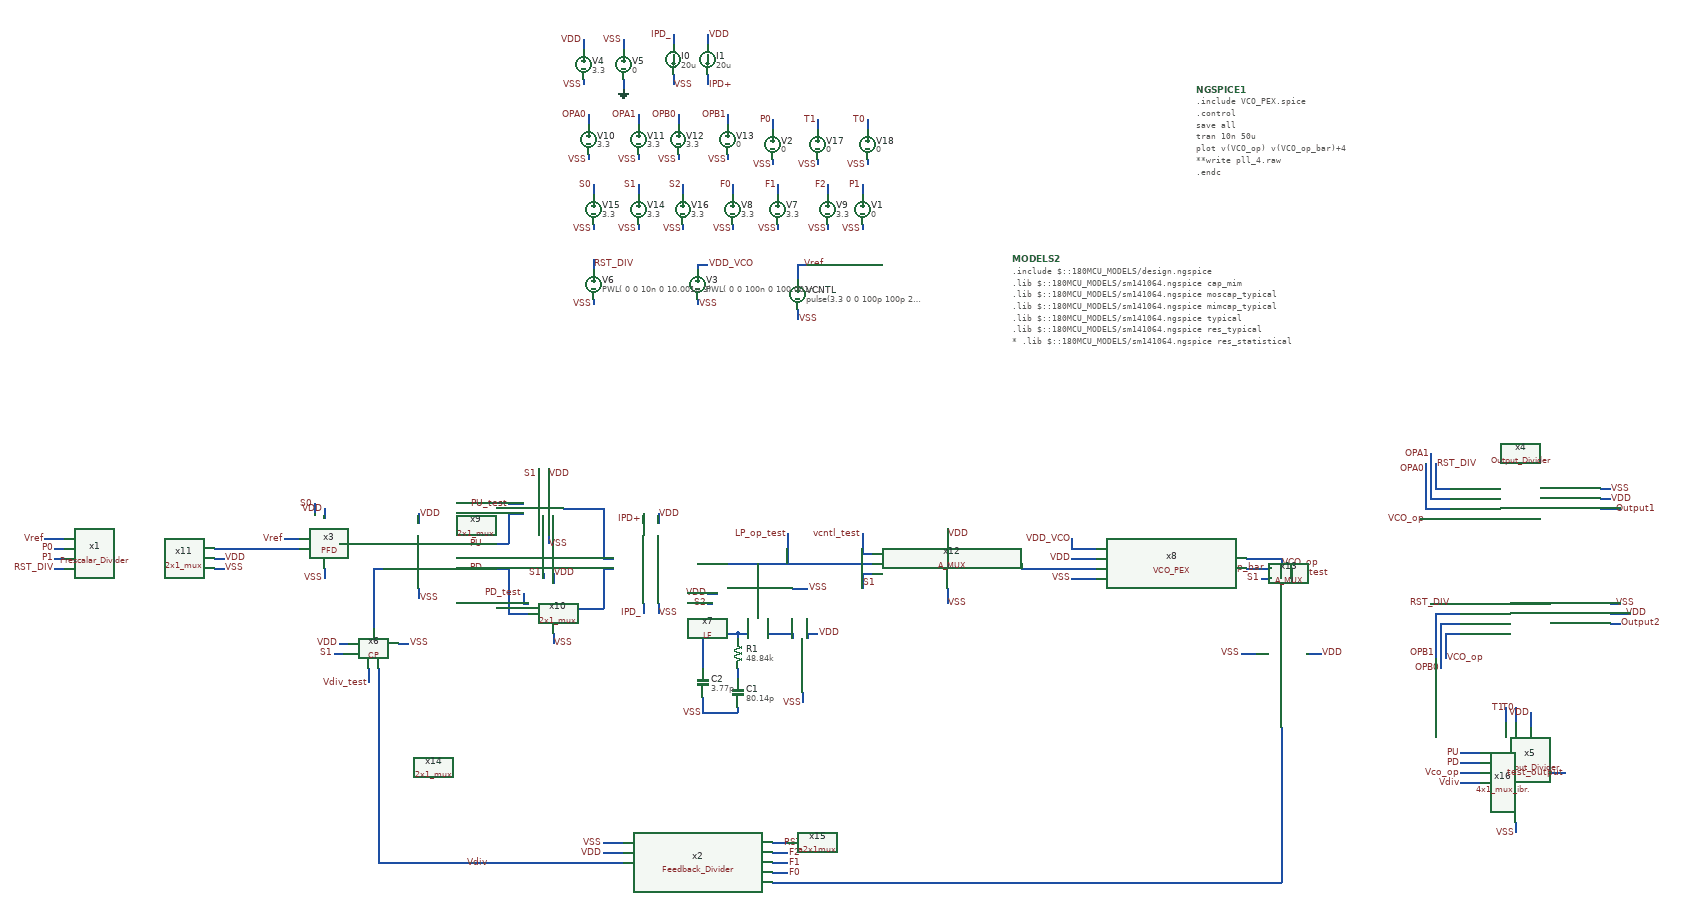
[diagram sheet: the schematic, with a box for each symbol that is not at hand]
v {xschem version=3.1.0 file_version=1.2
}
G {}
K {}
V {}
S {}
E {}
N 300 -1020 320 -1020 {
lab=P0}
N 300 -1000 320 -1000 {
lab=P1}
N 300 -980 320 -980 {
lab=RST_DIV}
N 620 -980 640 -980 {
lab=VSS}
N 620 -1000 640 -1000 {
lab=VDD}
N 1920 -1670 1920 -1660 {
lab=VSS}
N 1920 -1750 1920 -1730 {
lab=P1}
N 1740 -1800 1740 -1790 {
lab=VSS}
N 1740 -1880 1740 -1860 {
lab=P0}
N 1030 -1090 1030 -1070 {
lab=VDD}
N 1030 -940 1030 -920 {
lab=VSS}
N 940 -1030 960 -1030 {
lab=#net1}
N 940 -980 960 -980 {
lab=#net2}
N 1100 -980 1120 -980 {
lab=PD}
N 1120 -1030 1210 -1030 {
lab=PU}
N 1120 -980 1210 -980 {
lab=PD}
N 1150 -390 1440 -390 {
lab=Vdiv}
N 2340 -1020 2380 -1020 {
lab=VDD_VCO}
N 1100 -1030 1120 -1030 {
lab=PU}
N 1790 -1500 1790 -1480 {
lab=VSS}
N 1590 -1520 1590 -1510 {
lab=VSS}
N 1790 -1590 1810 -1590 {
lab=Vref}
N 1360 -1960 1360 -1950 {
lab=VSS}
N 1360 -2040 1360 -2020 {
lab=VDD}
N 1440 -2040 1440 -2020 {
lab=VSS}
N 1440 -1960 1440 -1940 {
lab=GND}
N 2340 -1040 2340 -1020 {
lab=VDD_VCO}
N 1400 -430 1440 -430 {
lab=VSS}
N 1400 -410 1440 -410 {
lab=VDD}
N 1740 -410 1770 -410 {
lab=F2}
N 1740 -430 1770 -430 {
lab=RST_DIV}
N 1380 -1520 1380 -1510 {
lab=VSS}
N 1380 -1600 1380 -1580 {
lab=RST_DIV}
N 2380 -1020 2390 -1020 {
lab=VDD_VCO}
N 1740 -370 1770 -370 {
lab=F0}
N 1740 -390 1770 -390 {
lab=F1}
N 1590 -1590 1590 -1580 {
lab=VDD_VCO}
N 1590 -1590 1610 -1590 {
lab=VDD_VCO}
N 1750 -1670 1750 -1660 {
lab=VSS}
N 1750 -1750 1750 -1730 {
lab=F1}
N 1660 -1670 1660 -1660 {
lab=VSS}
N 1660 -1750 1660 -1730 {
lab=F0}
N 1850 -1670 1850 -1660 {
lab=VSS}
N 1850 -1750 1850 -1730 {
lab=F2}
N 3070 -1140 3100 -1140 {
lab=RST_DIV}
N 3070 -1190 3070 -1140 {
lab=RST_DIV}
N 3040 -1080 3100 -1080 {
lab=VCO_op}
N 3060 -1120 3100 -1120 {
lab=OPA1}
N 3060 -1190 3060 -1120 {
lab=OPA1}
N 3050 -1100 3100 -1100 {
lab=OPA0}
N 3050 -1190 3050 -1100 {
lab=OPA0}
N 3400 -1140 3420 -1140 {
lab=VSS}
N 3400 -1120 3420 -1120 {
lab=VDD}
N 3400 -1100 3440 -1100 {
lab=Output1}
N 3060 -1210 3060 -1190 {
lab=OPA1}
N 3090 -850 3120 -850 {
lab=VCO_op}
N 3090 -850 3090 -800 {
lab=VCO_op}
N 3060 -910 3120 -910 {
lab=RST_DIV}
N 3080 -870 3120 -870 {
lab=OPB0}
N 3080 -870 3080 -800 {
lab=OPB0}
N 3070 -890 3120 -890 {
lab=OPB1}
N 3070 -890 3070 -800 {
lab=OPB1}
N 3420 -910 3440 -910 {
lab=VSS}
N 3420 -870 3440 -870 {
lab=Output2}
N 3420 -890 3460 -890 {
lab=VDD}
N 3080 -800 3080 -780 {
lab=OPB0}
N 1370 -1810 1370 -1800 {
lab=VSS}
N 1370 -1890 1370 -1870 {
lab=OPA0}
N 1470 -1810 1470 -1800 {
lab=VSS}
N 1470 -1890 1470 -1870 {
lab=OPA1}
N 1550 -1810 1550 -1800 {
lab=VSS}
N 1550 -1890 1550 -1870 {
lab=OPB0}
N 1650 -1810 1650 -1800 {
lab=VSS}
N 1650 -1890 1650 -1870 {
lab=OPB1}
N 1510 -1090 1510 -1070 {
lab=VDD}
N 1510 -910 1510 -890 {
lab=VSS}
N 1400 -1000 1420 -1000 {
lab=#net3}
N 1400 -980 1420 -980 {
lab=#net4}
N 1480 -1090 1480 -1070 {
lab=IPD+}
N 1480 -910 1480 -890 {
lab=IPD_}
N 1540 -1970 1540 -1950 {
lab=VSS}
N 1610 -1970 1610 -1950 {
lab=IPD+}
N 1540 -2050 1540 -2030 {
lab=IPD_}
N 1610 -2050 1610 -2030 {
lab=VDD}
N 710 -1020 740 -1020 {
lab=#net5}
N 280 -1040 310 -1040 {
lab=Vref}
N 620 -1020 690 -1020 {
lab=#net5}
N 690 -1020 710 -1020 {
lab=#net5}
N 310 -1040 320 -1040 {
lab=Vref}
N 1210 -980 1210 -890 {
lab=PD}
N 1210 -890 1250 -890 {
lab=PD}
N 1240 -910 1250 -910 {
lab=PD_test}
N 1240 -930 1240 -910 {
lab=PD_test}
N 1210 -1090 1210 -1030 {
lab=PU}
N 1210 -1090 1240 -1090 {
lab=PU}
N 1290 -1050 1290 -1030 {
lab=VSS}
N 1280 -970 1280 -960 {
lab=S1}
N 1300 -970 1300 -950 {
lab=VDD}
N 1320 -1100 1400 -1100 {
lab=#net3}
N 1400 -1100 1400 -1030 {
lab=#net3}
N 1400 -980 1400 -900 {
lab=#net4}
N 1330 -900 1400 -900 {
lab=#net4}
N 1400 -1030 1400 -1000 {
lab=#net3}
N 1270 -1180 1270 -1160 {
lab=S1}
N 1290 -1180 1290 -1150 {
lab=VDD}
N 1210 -1110 1240 -1110 {
lab=PU_test}
N 1300 -850 1300 -830 {
lab=VSS}
N 840 -980 840 -960 {
lab=VSS}
N 840 -1100 840 -1080 {
lab=VDD}
N 820 -1110 820 -1090 {
lab=S0}
N 740 -1020 790 -1020 {
lab=#net5}
N 760 -1040 790 -1040 {
lab=Vref}
N 1470 -1670 1470 -1660 {
lab=VSS}
N 1470 -1750 1470 -1730 {
lab=S1}
N 2090 -1060 2090 -1040 {
lab=VDD}
N 2090 -940 2090 -910 {
lab=VSS}
N 1920 -1010 1940 -1010 {
lab=vcntl_test}
N 1920 -1050 1920 -1010 {
lab=vcntl_test}
N 1920 -970 1940 -970 {
lab=S1}
N 1920 -970 1920 -940 {
lab=S1}
N 2780 -980 2780 -960 {
lab=Vo_test}
N 2760 -370 2760 -360 {
lab=#net6}
N 2680 -810 2710 -810 {
lab=VSS}
N 2810 -810 2840 -810 {
lab=VDD}
N 2720 -960 2740 -960 {
lab=S1}
N 2760 -360 2760 -350 {
lab=#net6}
N 2410 -350 2760 -350 {
lab=#net6}
N 1740 -350 2410 -350 {
lab=#net6}
N 1790 -1590 1790 -1560 {
lab=Vref}
N 2240 -980 2390 -980 {
lab=#net7}
N 2240 -990 2240 -980 {
lab=#net7}
N 2340 -1000 2390 -1000 {
lab=VDD}
N 2340 -960 2390 -960 {
lab=VSS}
N 2690 -1000 2760 -1000 {
lab=VCO_op}
N 2690 -980 2740 -980 {
lab=VCO_op_bar}
N 2760 -1000 2760 -960 {
lab=VCO_op}
N 870 -1030 930 -1030 {
lab=#net1}
N 990 -830 1010 -830 {
lab=VSS}
N 870 -830 890 -830 {
lab=VDD}
N 860 -810 880 -810 {
lab=S1}
N 950 -780 950 -730 {
lab=Vdiv}
N 930 -780 930 -750 {
lab=Vdiv_test}
N 940 -920 940 -860 {
lab=#net2}
N 950 -730 950 -680 {
lab=Vdiv}
N 940 -980 940 -920 {
lab=#net2}
N 930 -1030 940 -1030 {
lab=#net1}
N 1380 -1670 1380 -1660 {
lab=VSS}
N 1380 -1750 1380 -1730 {
lab=S0}
N 1800 -730 1800 -710 {
lab=VSS}
N 1810 -850 1810 -840 {
lab=VDD}
N 1810 -850 1830 -850 {
lab=VDD}
N 1610 -930 1630 -930 {
lab=VDD}
N 1780 -940 1810 -940 {
lab=VSS}
N 1600 -720 1600 -690 {
lab=VSS}
N 1600 -690 1670 -690 {
lab=VSS}
N 1600 -850 1600 -780 {
lab=#net8}
N 1600 -850 1670 -850 {
lab=#net8}
N 1670 -850 1670 -840 {
lab=#net8}
N 1670 -780 1670 -760 {
lab=#net9}
N 1670 -700 1670 -690 {
lab=VSS}
N 1670 -850 1690 -850 {
lab=#net8}
N 1690 -880 1690 -850 {
lab=#net8}
N 1780 -850 1780 -840 {
lab=#net10}
N 1730 -850 1780 -850 {
lab=#net10}
N 1730 -880 1730 -850 {
lab=#net10}
N 1710 -990 1710 -980 {
lab=LP_op_test}
N 950 -390 1150 -390 {
lab=Vdiv}
N 950 -680 950 -560 {
lab=Vdiv}
N 2760 -490 2760 -370 {
lab=#net6}
N 950 -560 950 -390 {
lab=Vdiv}
N 2760 -660 2760 -500 {
lab=#net6}
N 2760 -500 2760 -490 {
lab=#net6}
N 1560 -1670 1560 -1660 {
lab=VSS}
N 1560 -1750 1560 -1730 {
lab=S2}
N 1610 -910 1620 -910 {
lab=S2}
N 1590 -990 1940 -990 {
lab=LP_op_test}
N 3120 -610 3160 -610 {
lab=#net11}
N 3120 -590 3160 -590 {
lab=#net12}
N 3120 -570 3160 -570 {
lab=#net13}
N 3120 -550 3160 -550 {
lab=#net14}
N 1770 -1050 1770 -990 {}
N 3260 -690 3260 -660 {}
N 3230 -700 3230 -670 {}
N 3210 -700 3210 -670 {}
N 3230 -470 3230 -450 {}
N 3300 -570 3330 -570 {}
N 1830 -1800 1830 -1790 {
lab=VSS}
N 1830 -1880 1830 -1860 {
lab=P1}
N 1930 -1800 1930 -1790 {
lab=VSS}
N 1930 -1880 1930 -1860 {
lab=P0}
C {devices/lab_pin.sym} 300 -1000 0 0 {name=p139 sig_type=std_logic lab=P1}
C {devices/lab_pin.sym} 300 -1020 0 0 {name=p140 sig_type=std_logic lab=P0}
C {devices/lab_pin.sym} 280 -1040 0 0 {name=p141 sig_type=std_logic lab=Vref
}
C {devices/lab_pin.sym} 640 -980 2 0 {name=p142 sig_type=std_logic lab=VSS}
C {devices/lab_pin.sym} 640 -1000 2 0 {name=p143 sig_type=std_logic lab=VDD}
C {devices/lab_pin.sym} 300 -980 0 0 {name=p144 sig_type=std_logic lab=RST_DIV}
C {devices/vsource.sym} 1920 -1700 0 0 {name=V1 value=0}
C {devices/lab_wire.sym} 1920 -1660 0 0 {name=p1 sig_type=std_logic lab=VSS
}
C {devices/lab_wire.sym} 1920 -1750 0 0 {name=p2 sig_type=std_logic lab=P1}
C {devices/vsource.sym} 1740 -1830 0 0 {name=V2 value=0}
C {devices/lab_wire.sym} 1740 -1790 0 0 {name=p3 sig_type=std_logic lab=VSS
}
C {devices/lab_wire.sym} 1740 -1880 0 0 {name=p4 sig_type=std_logic lab=P0}
C {PFD.sym} 740 -820 0 0 {name=x3}
C {devices/lab_pin.sym} 1030 -1090 2 0 {name=p9 sig_type=std_logic lab=VDD}
C {devices/lab_wire.sym} 1030 -920 2 0 {name=p10 sig_type=std_logic lab=VSS}
C {devices/lab_pin.sym} 1170 -390 1 0 {name=p28 sig_type=std_logic lab=Vdiv
}
C {devices/vsource.sym} 1790 -1530 0 0 {name=VCNTL value="pulse(3.3 0 0 100p 100p 250n 500n)"}
C {devices/vsource.sym} 1590 -1550 0 0 {name=V3 value=" PWL( 0 0 100n 0 100.001n 3.3)"}
C {devices/code_shown.sym} 2590 -1940 0 1 {name=NGSPICE1 only_toplevel=true
value="
.include "VCO_PEX.spice"
.control
save all
tran 10n 50u 
plot v(VCO_op) v(VCO_op_bar)+4
**write pll_4.raw
.endc
"}
C {devices/vsource.sym} 1360 -1990 0 0 {name=V4 value=3.3}
C {devices/vsource.sym} 1440 -1990 0 0 {name=V5 value=0}
C {devices/lab_wire.sym} 1440 -2040 0 0 {name=p7 sig_type=std_logic lab=VSS}
C {devices/lab_wire.sym} 1360 -1950 0 0 {name=p8 sig_type=std_logic lab=VSS
}
C {devices/lab_wire.sym} 1360 -2040 0 0 {name=p11 sig_type=std_logic lab=VDD}
C {devices/gnd.sym} 1440 -1940 0 0 {name=l3 lab=GND}
C {devices/lab_pin.sym} 2340 -1040 0 0 {name=p12 sig_type=std_logic lab=VDD_VCO}
C {devices/lab_pin.sym} 2730 -980 1 0 {name=p13 sig_type=std_logic lab=VCO_op_bar
}
C {devices/lab_pin.sym} 1400 -410 0 0 {name=p14 sig_type=std_logic lab=VDD}
C {devices/lab_wire.sym} 1400 -430 1 0 {name=p15 sig_type=std_logic lab=VSS}
C {devices/lab_pin.sym} 1610 -1590 2 0 {name=p16 sig_type=std_logic lab=VDD_VCO}
C {devices/lab_pin.sym} 1800 -1590 2 0 {name=p17 sig_type=std_logic lab=Vref
}
C {devices/lab_wire.sym} 1380 -1510 0 0 {name=p18 sig_type=std_logic lab=VSS
}
C {devices/vsource.sym} 1380 -1550 0 0 {name=V6 value=" PWL( 0 0 10n 0 10.001n 3)"}
C {devices/lab_pin.sym} 1770 -1050 1 0 {name=p19 sig_type=std_logic lab=LP_op_test
}
C {devices/lab_pin.sym} 1160 -1030 1 0 {name=p20 sig_type=std_logic lab=PU}
C {devices/lab_pin.sym} 1160 -980 1 0 {name=p21 sig_type=std_logic lab=PD}
C {Feedback_Divider.sym} 1590 -390 0 1 {name=x2}
C {devices/lab_pin.sym} 1770 -370 2 0 {name=p22 sig_type=std_logic lab=F0}
C {devices/lab_pin.sym} 1770 -390 2 0 {name=p23 sig_type=std_logic lab=F1}
C {devices/lab_pin.sym} 1770 -410 2 0 {name=p24 sig_type=std_logic lab=F2}
C {devices/vsource.sym} 1750 -1700 0 0 {name=V7 value=3.3}
C {devices/lab_wire.sym} 1750 -1660 0 0 {name=p26 sig_type=std_logic lab=VSS
}
C {devices/lab_wire.sym} 1750 -1750 0 0 {name=p27 sig_type=std_logic lab=F1}
C {devices/vsource.sym} 1660 -1700 0 0 {name=V8 value=3.3}
C {devices/lab_wire.sym} 1660 -1660 0 0 {name=p25 sig_type=std_logic lab=VSS
}
C {devices/lab_wire.sym} 1660 -1750 0 0 {name=p29 sig_type=std_logic lab=F0}
C {devices/vsource.sym} 1850 -1700 0 0 {name=V9 value=3.3}
C {devices/lab_wire.sym} 1850 -1660 0 0 {name=p30 sig_type=std_logic lab=VSS
}
C {devices/lab_wire.sym} 1850 -1750 0 0 {name=p31 sig_type=std_logic lab=F2}
C {devices/lab_pin.sym} 3420 -1120 2 0 {name=p32 sig_type=std_logic lab=VDD}
C {devices/lab_pin.sym} 3420 -1140 2 0 {name=p33 sig_type=std_logic lab=VSS}
C {devices/lab_wire.sym} 3050 -1180 0 0 {name=p82 sig_type=std_logic lab=OPA0}
C {devices/lab_wire.sym} 3060 -1210 0 0 {name=p83 sig_type=std_logic lab=OPA1}
C {devices/lab_pin.sym} 3070 -1190 2 0 {name=p34 sig_type=std_logic lab=RST_DIV}
C {devices/lab_pin.sym} 3430 -1100 2 0 {name=p84 sig_type=std_logic lab=Output1}
C {devices/lab_pin.sym} 3450 -890 0 1 {name=p85 sig_type=std_logic lab=VDD}
C {devices/lab_pin.sym} 3430 -910 0 1 {name=p86 sig_type=std_logic lab=VSS}
C {devices/lab_wire.sym} 3070 -810 2 1 {name=p87 sig_type=std_logic lab=OPB1}
C {devices/lab_wire.sym} 3080 -780 2 1 {name=p88 sig_type=std_logic lab=OPB0}
C {devices/lab_pin.sym} 3440 -870 0 1 {name=p90 sig_type=std_logic lab=Output2}
C {Output_Divider.sym} 3270 -880 0 0 {name=x5}
C {devices/lab_pin.sym} 3100 -910 1 0 {name=p35 sig_type=std_logic lab=RST_DIV}
C {devices/lab_pin.sym} 3090 -800 2 0 {name=p37 sig_type=std_logic lab=VCO_op
}
C {devices/lab_pin.sym} 3050 -1080 2 1 {name=p40 sig_type=std_logic lab=VCO_op
}
C {devices/vsource.sym} 1370 -1840 0 0 {name=V10 value=3.3}
C {devices/lab_wire.sym} 1370 -1800 0 0 {name=p41 sig_type=std_logic lab=VSS
}
C {devices/lab_wire.sym} 1370 -1890 0 0 {name=p42 sig_type=std_logic lab=OPA0}
C {devices/vsource.sym} 1470 -1840 0 0 {name=V11 value=3.3}
C {devices/lab_wire.sym} 1470 -1800 0 0 {name=p43 sig_type=std_logic lab=VSS
}
C {devices/lab_wire.sym} 1470 -1890 0 0 {name=p44 sig_type=std_logic lab=OPA1}
C {devices/vsource.sym} 1550 -1840 0 0 {name=V12 value=3.3}
C {devices/lab_wire.sym} 1550 -1800 0 0 {name=p45 sig_type=std_logic lab=VSS
}
C {devices/lab_wire.sym} 1550 -1890 0 0 {name=p46 sig_type=std_logic lab=OPB0
}
C {devices/vsource.sym} 1650 -1840 0 0 {name=V13 value=0}
C {devices/lab_wire.sym} 1650 -1800 0 0 {name=p47 sig_type=std_logic lab=VSS
}
C {devices/lab_wire.sym} 1650 -1890 0 0 {name=p48 sig_type=std_logic lab=OPB1}
C {devices/lab_pin.sym} 1380 -1590 2 0 {name=p38 sig_type=std_logic lab=RST_DIV}
C {devices/lab_pin.sym} 1760 -430 2 0 {name=p39 sig_type=std_logic lab=RST_DIV}
C {devices/lab_wire.sym} 1510 -890 2 0 {name=p49 sig_type=std_logic lab=VSS}
C {devices/lab_pin.sym} 1510 -1090 2 0 {name=p50 sig_type=std_logic lab=VDD}
C {CP.sym} 930 -790 0 0 {name=x6}
C {devices/lab_wire.sym} 1480 -1080 0 0 {name=p52 sig_type=std_logic lab=IPD+}
C {devices/lab_wire.sym} 1480 -890 0 0 {name=p53 sig_type=std_logic lab=IPD_}
C {devices/isource.sym} 1540 -2000 0 0 {name=I0 value=20u}
C {devices/isource.sym} 1610 -2000 0 0 {name=I1 value=20u}
C {devices/lab_wire.sym} 1540 -2050 0 0 {name=p54 sig_type=std_logic lab=IPD_}
C {devices/lab_wire.sym} 1610 -1950 2 0 {name=p55 sig_type=std_logic lab=IPD+}
C {devices/lab_wire.sym} 1540 -1950 2 0 {name=p56 sig_type=std_logic lab=VSS}
C {devices/lab_wire.sym} 1610 -2050 2 0 {name=p57 sig_type=std_logic lab=VDD}
C {Output_Divider.sym} 3250 -1110 0 0 {name=x4}
C {devices/code_shown.sym} 2220 -1600 0 0 {name=MODELS2 only_toplevel=true
format="tcleval( @value )"
value="
.include $::180MCU_MODELS/design.ngspice
.lib $::180MCU_MODELS/sm141064.ngspice cap_mim
.lib $::180MCU_MODELS/sm141064.ngspice moscap_typical
.lib $::180MCU_MODELS/sm141064.ngspice mimcap_typical
.lib $::180MCU_MODELS/sm141064.ngspice typical
.lib $::180MCU_MODELS/sm141064.ngspice res_typical
* .lib $::180MCU_MODELS/sm141064.ngspice res_statistical
"}
C {Prescalar_Divider.sym} 470 -1010 2 1 {name=x1}
C {devices/lab_wire.sym} 1590 -1510 2 0 {name=p5 sig_type=std_logic lab=VSS
}
C {devices/lab_wire.sym} 1790 -1480 2 0 {name=p6 sig_type=std_logic lab=VSS
}
C {2x1_mux.sym} 1040 -980 0 0 {name=x9}
C {2x1_mux.sym} 1050 -780 0 0 {name=x10}
C {devices/lab_pin.sym} 1210 -1110 0 0 {name=p60 sig_type=std_logic lab=PU_test
}
C {devices/lab_pin.sym} 1240 -930 1 0 {name=p61 sig_type=std_logic lab=PD_test
}
C {devices/lab_pin.sym} 1290 -1170 2 0 {name=p62 sig_type=std_logic lab=VDD}
C {devices/lab_pin.sym} 1300 -970 2 0 {name=p63 sig_type=std_logic lab=VDD}
C {devices/lab_wire.sym} 1300 -830 2 0 {name=p64 sig_type=std_logic lab=VSS}
C {devices/lab_wire.sym} 1290 -1030 2 0 {name=p65 sig_type=std_logic lab=VSS}
C {devices/lab_pin.sym} 1270 -1170 1 0 {name=p106 sig_type=std_logic lab=S1}
C {devices/lab_pin.sym} 1280 -970 1 0 {name=p66 sig_type=std_logic lab=S1}
C {2x1_mux.sym} 590 -910 0 0 {name=x11}
C {devices/lab_wire.sym} 840 -960 3 0 {name=p67 sig_type=std_logic lab=VSS}
C {devices/lab_pin.sym} 840 -1100 3 1 {name=p68 sig_type=std_logic lab=VDD}
C {devices/lab_pin.sym} 820 -1110 1 0 {name=p69 sig_type=std_logic lab=S0}
C {devices/lab_pin.sym} 760 -1040 1 0 {name=p70 sig_type=std_logic lab=Vref
}
C {devices/vsource.sym} 1470 -1700 0 0 {name=V14 value=3.3}
C {devices/lab_wire.sym} 1470 -1660 0 0 {name=p71 sig_type=std_logic lab=VSS
}
C {devices/lab_wire.sym} 1470 -1750 0 0 {name=p72 sig_type=std_logic lab=S1}
C {A_MUX.sym} 2090 -990 0 0 {name=x12}
C {devices/lab_pin.sym} 2090 -1050 2 0 {name=p73 sig_type=std_logic lab=VDD}
C {devices/lab_wire.sym} 2090 -910 2 0 {name=p74 sig_type=std_logic lab=VSS}
C {devices/lab_pin.sym} 1920 -950 2 0 {name=p75 sig_type=std_logic lab=S1}
C {devices/lab_pin.sym} 1920 -1050 0 0 {name=p76 sig_type=std_logic lab=vcntl_test
}
C {devices/lab_pin.sym} 2760 -990 2 0 {name=p77 sig_type=std_logic lab=VCO_op
}
C {devices/lab_pin.sym} 2780 -970 2 0 {name=p78 sig_type=std_logic lab=Vo_test
}
C {A_MUX.sym} 2760 -810 1 0 {name=x13}
C {devices/lab_pin.sym} 2720 -960 0 0 {name=p79 sig_type=std_logic lab=S1}
C {devices/lab_wire.sym} 2680 -810 0 0 {name=p36 sig_type=std_logic lab=VSS}
C {devices/lab_pin.sym} 2840 -810 2 0 {name=p80 sig_type=std_logic lab=VDD}
C {devices/lab_pin.sym} 2340 -1000 0 0 {name=p81 sig_type=std_logic lab=VDD}
C {devices/lab_wire.sym} 2340 -960 2 1 {name=p89 sig_type=std_logic lab=VSS}
C {2x1_mux.sym} 1060 -580 3 0 {name=x14}
C {devices/lab_wire.sym} 1010 -830 2 0 {name=p91 sig_type=std_logic lab=VSS}
C {devices/lab_pin.sym} 870 -830 2 1 {name=p92 sig_type=std_logic lab=VDD}
C {devices/lab_pin.sym} 860 -810 0 0 {name=p93 sig_type=std_logic lab=S1}
C {devices/lab_pin.sym} 930 -750 0 0 {name=p94 sig_type=std_logic lab=Vdiv_test

}
C {devices/vsource.sym} 1380 -1700 0 0 {name=V15 value=3.3}
C {devices/lab_wire.sym} 1380 -1660 0 0 {name=p95 sig_type=std_logic lab=VSS
}
C {devices/lab_wire.sym} 1380 -1750 0 0 {name=p96 sig_type=std_logic lab=S0}
C {devices/lab_wire.sym} 1800 -710 2 1 {name=p58 sig_type=std_logic lab=VSS}
C {devices/lab_wire.sym} 1830 -850 0 1 {name=p98 sig_type=std_logic lab=VDD}
C {devices/lab_wire.sym} 1810 -940 2 0 {name=p99 sig_type=std_logic lab=VSS}
C {devices/lab_wire.sym} 1610 -930 2 1 {name=p100 sig_type=std_logic lab=VDD}
C {devices/lab_wire.sym} 1610 -910 1 1 {name=p101 sig_type=std_logic lab=S2}
C {devices/capa.sym} 1670 -730 0 0 {name=C1
m=1
value=80.14p
footprint=1206
device="ceramic capacitor"}
C {devices/capa.sym} 1600 -750 0 0 {name=C2
m=1
value=3.77p
footprint=1206
device="ceramic capacitor"}
C {devices/res.sym} 1670 -810 0 0 {name=R1
value=48.84k
footprint=1206
device=resistor
m=1}
C {devices/lab_wire.sym} 1600 -690 2 1 {name=p102 sig_type=std_logic lab=VSS}
C {LF.sym} 1940 -680 0 1 {name=x7}
C {a2x1mux.sym} 1870 -560 3 0 {name=x15}
C {devices/vsource.sym} 1560 -1700 0 0 {name=V16 value=3.3}
C {devices/lab_wire.sym} 1560 -1660 0 0 {name=p51 sig_type=std_logic lab=VSS
}
C {devices/lab_wire.sym} 1560 -1750 0 0 {name=p59 sig_type=std_logic lab=S2}
C {VCO_PEX.sym} 2540 -990 0 0 {name=x8}
C {4x1_mux_ibr..sym} 2880 -460 0 0 {name=x16}
C {devices/lab_pin.sym} 3120 -610 0 0 {name=p97 sig_type=std_logic lab=PU}
C {devices/lab_pin.sym} 3120 -590 0 0 {name=p103 sig_type=std_logic lab=PD}
C {devices/lab_pin.sym} 3120 -570 0 0 {name=p104 sig_type=std_logic lab=Vco_op
}
C {devices/lab_pin.sym} 3120 -550 0 0 {name=p105 sig_type=std_logic lab=Vdiv
}
C {devices/lab_pin.sym} 3210 -700 1 0 {name=p107 sig_type=std_logic lab=T1}
C {devices/lab_pin.sym} 3230 -700 1 0 {name=p108 sig_type=std_logic lab=T0}
C {devices/lab_pin.sym} 3260 -690 3 1 {name=p109 sig_type=std_logic lab=VDD}
C {devices/lab_wire.sym} 3230 -450 3 0 {name=p110 sig_type=std_logic lab=VSS}
C {devices/lab_pin.sym} 3330 -570 1 1 {name=p111 sig_type=std_logic lab=test_output}
C {devices/vsource.sym} 1830 -1830 0 0 {name=V17 value=0}
C {devices/lab_wire.sym} 1830 -1790 0 0 {name=p112 sig_type=std_logic lab=VSS
}
C {devices/lab_wire.sym} 1830 -1880 0 0 {name=p113 sig_type=std_logic lab=T1}
C {devices/vsource.sym} 1930 -1830 0 0 {name=V18 value=0}
C {devices/lab_wire.sym} 1930 -1790 0 0 {name=p114 sig_type=std_logic lab=VSS
}
C {devices/lab_wire.sym} 1930 -1880 0 0 {name=p115 sig_type=std_logic lab=T0}
